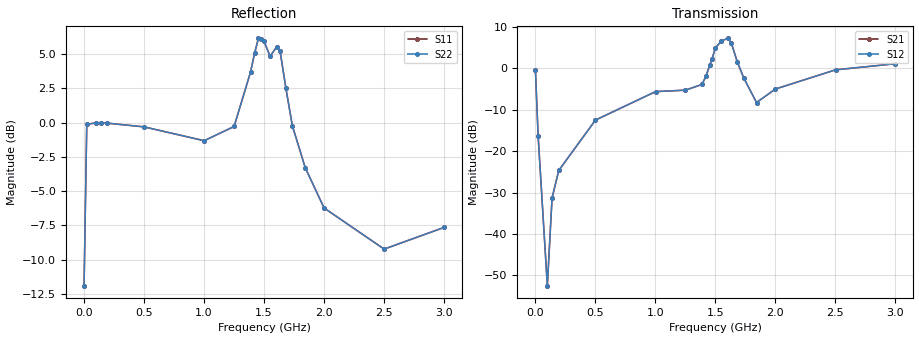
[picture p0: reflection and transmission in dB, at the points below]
!s-Parameter Generated by FASTRON Sdn. Bhd.
!FASTRON P/N : MICC-4R4X
!Keysight Technologies,E4991B,MY54100416,A.01.15
!Date: Fri Aug 28 10:22:52 2026
!Version  : Rev00 Fri Aug 28 10:22:52 2026
!Data & Calibration Information:
!PortZ  Port1:50+j0  Port2:50+j0
!When reading, reference impedance value at option line is always used.
!Remarks : This data is being provided solely for informational purposes.
!Freq	S11	S21	S12	S22
# Hz S dB R 50
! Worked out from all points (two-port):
!   1601 points, 1 MHz to 3 GHz, reference 50 ohm
!   highest |S21| = 7.23 dB at 1.605 GHz (marker M1); lowest = -52.5 dB at 100.3 MHz (marker M2)
!   |S21| within 3 dB of the highest: 1.492 GHz to 1.658 GHz (166 MHz wide, 10.5 % of centre)
!   lowest |S11| = -11.9 dB at 1 MHz (marker M3), VSWR 1.68, Z = 50.7 + j26.5 ohm
!   |S11| at or under -10 dB: start of sweep to 1.477 MHz
!   |S22| runs from -11.9 to 6.2 dB; largest |S21 - S12| = 0
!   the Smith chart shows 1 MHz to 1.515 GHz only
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1000000  -11.90 73.8  -0.35 -14.7  -0.35 -14.7  -11.90 73.8
2.34925e7  -0.12 8.8  -16.28 -80.3  -16.28 -80.3  -0.12 8.8
1.003419e8  -0.02 -0.0  -52.48 16.9  -52.48 16.9  -0.02 -0.0
1.397038e8  -0.02 -1.6  -31.28 83.5  -31.28 83.5  -0.02 -1.6
1.95935e8  -0.04 -3.4  -24.64 84.2  -24.64 84.2  -0.04 -3.4
5.014581e8  -0.31 -13.7  -12.50 74.8  -12.50 74.8  -0.31 -13.7
1.001916e9  -1.32 -31.5  -5.63 59.2  -5.63 59.2  -1.32 -31.5
1.251208e9  -0.28 -32.1  -5.27 70.8  -5.27 70.8  -0.28 -32.1
1.388038e9  3.69 -16.6  -3.90 136.9  -3.90 136.9  3.69 -16.6
1.421776e9  5.06 -4.5  -1.96 169.8  -1.96 169.8  5.06 -4.5
1.453641e9  6.15 15.1  0.80 -151.2  0.80 -151.2  6.15 15.1
1.472384e9  6.10 32.8  2.25 -122.5  2.25 -122.5  6.10 32.8
1.5005e9  5.94 62.6  4.92 -87.1  4.92 -87.1  5.94 62.6
1.551108e9  4.84 99.2  6.63 -53.5  6.63 -53.5  4.84 99.2
1.605465e9  5.53 100.7  7.23 -54.0  7.23 -54.0  5.53 100.7
1.633581e9  5.26 85.2  6.08 -65.1  6.08 -65.1  5.26 85.2
1.682314e9  2.53 60.2  1.64 -73.9  1.64 -73.9  2.53 60.2
1.736671e9  -0.23 45.5  -2.33 -65.4  -2.33 -65.4  -0.23 45.5
1.843511e9  -3.28 15.6  -8.26 -28.4  -8.26 -28.4  -3.28 15.6
2.000958e9  -6.23 -19.1  -5.00 16.5  -5.00 16.5  -6.23 -19.1
2.501416e9  -9.23 -73.1  -0.37 20.2  -0.37 20.2  -9.23 -73.1
3e9  -7.65 -98.1  1.10 21.2  1.10 21.2  -7.65 -98.1
